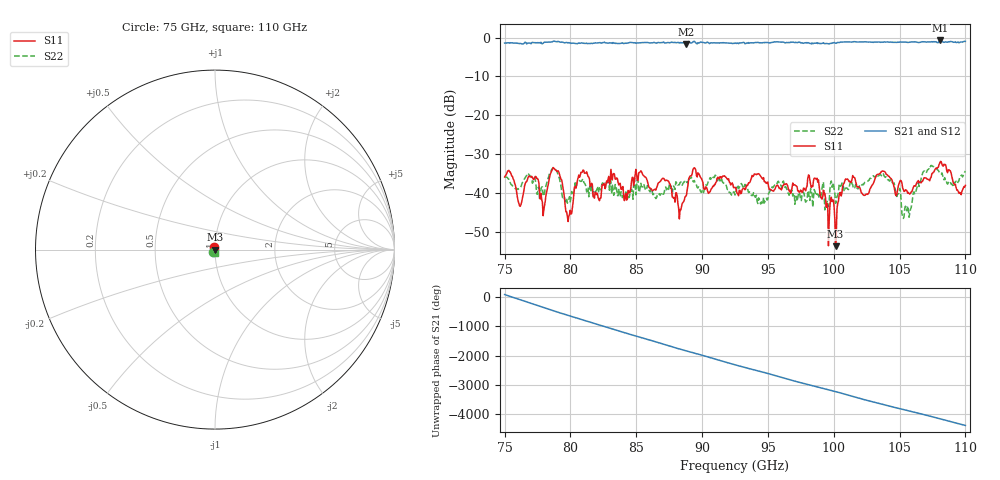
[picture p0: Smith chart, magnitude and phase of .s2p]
!Created with skrf (http://scikit-rf.org).
# GHz S RI R 50.0
!freq ReS11 ImS11 ReS21 ImS21 ReS12 ImS12 ReS22 ImS22
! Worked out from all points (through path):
!   647 points, 75 GHz to 110 GHz, reference 50 ohm
!   highest |S21| = -0.74 dB at 108.1 GHz (marker M1); lowest = -1.7 dB at 88.82 GHz (marker M2)
!   lowest |S11| = -53.7 dB at 100.1 GHz (marker M3), VSWR 1.00, Z = 49.8 - j0.0728 ohm
!   |S11| at or under -10 dB: start of sweep to end of sweep
!   |S22| runs from -46.5 to -32.9 dB; largest |S21 - S12| = 0
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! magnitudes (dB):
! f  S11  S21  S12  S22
! 75 GHz  -35.9  -1.4  -1.4  -35.9
! 76.14 GHz  -43.3  -1.6  -1.6  -38.8
! 77.44 GHz  -36.3  -1.4  -1.4  -40.2
! 77.98 GHz  -44.3  -1.3  -1.3  -40.7
! 78.85 GHz  -34.0  -1.0  -1.0  -34.1
! 79.93 GHz  -45.5  -1.4  -1.4  -40.9
! 80.85 GHz  -34.7  -1.4  -1.4  -37.0
! 82.15 GHz  -41.6  -1.3  -1.3  -39.9
! 83.24 GHz  -35.1  -1.3  -1.3  -38.8
! 84.21 GHz  -40.1  -1.5  -1.5  -39.7
! 86.7 GHz  -37.3  -1.3  -1.3  -40.6
! 88.33 GHz  -44.3  -1.3  -1.3  -37.3
! 88.82 GHz  -40.5  -1.7  -1.7  -37.3
! 89.36 GHz  -33.6  -1.0  -1.0  -37.2
! 92.5 GHz  -38.6  -1.4  -1.4  -40.5
! 98.35 GHz  -38.2  -1.4  -1.4  -40.1
! 100.1 GHz  -53.7  -1.5  -1.5  -42.6
! 100.9 GHz  -36.4  -1.1  -1.1  -38.7
! 104.2 GHz  -35.7  -1.2  -1.2  -36.8
! 105.3 GHz  -39.6  -1.2  -1.2  -46.1
! 108.1 GHz  -31.9  -0.7  -0.7  -35.1
! 110 GHz  -38.0  -1.0  -1.0  -34.3
